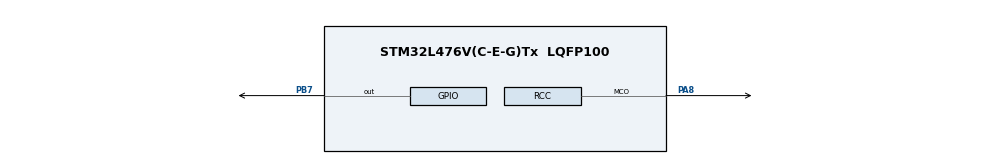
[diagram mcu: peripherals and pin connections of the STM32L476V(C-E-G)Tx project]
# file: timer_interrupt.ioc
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Mcu.Family=STM32L4
RCC.MSI_VALUE=4000000
PH0-OSC_IN\ (PH0).Signal=RCC_OSC_IN
PH1-OSC_OUT\ (PH1).Signal=RCC_OSC_OUT
ProjectManager.StackSize=0x400
ProjectManager.TargetToolchain=STM32CubeIDE
RCC.LSE_VALUE=32768
PH1-OSC_OUT\ (PH1).Mode=HSE-External-Oscillator
RCC.HSE_VALUE=8000000
board=custom
RCC.VCOOutputFreq_Value=32000000
VP_TIM2_VS_ClockSourceINT.Mode=Internal
NVIC.TIM2_IRQn=true\:0\:0\:false\:false\:true\:true\:true
PB7.Signal=GPIO_Output
PA8.Signal=RCC_MCO
TIM2.Period=7200
Mcu.Name=STM32L476V(C-E-G)Tx
Mcu.Package=LQFP100
TIM2.Prescaler=1000
ProjectManager.HeapSize=0x200
RCC.HSI_VALUE=16000000
NVIC.PriorityGroup=NVIC_PRIORITYGROUP_4
TIM2.AutoReloadPreload=TIM_AUTORELOAD_PRELOAD_ENABLE
PA8.Mode=Clock-out
PH0-OSC_IN\ (PH0).Mode=HSE-External-Oscillator

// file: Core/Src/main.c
/* USER CODE BEGIN Header */
/**
  ******************************************************************************
  * @file           : main.c
  * @brief          : Main program body
  ******************************************************************************
  * @attention
  *
  * <h2><center>&copy; Copyright (c) 2020 STMicroelectronics.
  * All rights reserved.</center></h2>
  *
  * This software component is licensed by ST under BSD 3-Clause license,
  * the "License"; You may not use this file except in compliance with the
  * License. You may obtain a copy of the License at:
  *                        opensource.org/licenses/BSD-3-Clause
  *
  ******************************************************************************
  */
/* USER CODE END Header */
#include "main.h"

TIM_HandleTypeDef htim2;

void SystemClock_Config(void);
static void MX_GPIO_Init(void);
static void MX_TIM2_Init(void);

int main(void)
{

  /* MCU Configuration--------------------------------------------------------*/

  /* Reset of all peripherals, Initializes the Flash interface and the Systick. */
  HAL_Init();

  /* Configure the system clock */
  SystemClock_Config();

  /* Initialize all configured peripherals */
  MX_GPIO_Init();
  MX_TIM2_Init();
  /* USER CODE BEGIN 2 */
  HAL_TIM_Base_Start_IT(&htim2);
  /* USER CODE END 2 */

  /* Infinite loop */
  while (1)
  {

  }
}

void SystemClock_Config(void)
{
	  RCC_OscInitTypeDef RCC_OscInitStruct = {0};
	  RCC_ClkInitTypeDef RCC_ClkInitStruct = {0};
	  RCC_PeriphCLKInitTypeDef PeriphClkInit = {0};

	  RCC_OscInitStruct.OscillatorType = RCC_OSCILLATORTYPE_MSI;
	  RCC_OscInitStruct.MSIState = RCC_MSI_ON;
	  RCC_OscInitStruct.MSICalibrationValue = 0;
	  RCC_OscInitStruct.MSIClockRange = RCC_MSIRANGE_6;
	  RCC_OscInitStruct.PLL.PLLState = RCC_PLL_ON;
	  RCC_OscInitStruct.PLL.PLLSource = RCC_PLLSOURCE_MSI;
	  RCC_OscInitStruct.PLL.PLLM = 1;
	  RCC_OscInitStruct.PLL.PLLN = 40;
	  RCC_OscInitStruct.PLL.PLLP = RCC_PLLP_DIV7;
	  RCC_OscInitStruct.PLL.PLLQ = RCC_PLLQ_DIV2;
	  RCC_OscInitStruct.PLL.PLLR = RCC_PLLR_DIV2;
	  if (HAL_RCC_OscConfig(&RCC_OscInitStruct) != HAL_OK) {
	    Error_Handler();
	  }
	  RCC_ClkInitStruct.ClockType = RCC_CLOCKTYPE_HCLK|RCC_CLOCKTYPE_SYSCLK
	                              |RCC_CLOCKTYPE_PCLK1|RCC_CLOCKTYPE_PCLK2;
	  RCC_ClkInitStruct.SYSCLKSource = RCC_SYSCLKSOURCE_PLLCLK;
	  RCC_ClkInitStruct.AHBCLKDivider = RCC_SYSCLK_DIV1;
	  RCC_ClkInitStruct.APB1CLKDivider = RCC_HCLK_DIV1;
	  RCC_ClkInitStruct.APB2CLKDivider = RCC_HCLK_DIV1;

	  if (HAL_RCC_ClockConfig(&RCC_ClkInitStruct, FLASH_LATENCY_4) != HAL_OK) {
	    Error_Handler();
	  }
	  PeriphClkInit.PeriphClockSelection = RCC_PERIPHCLK_USART1|RCC_PERIPHCLK_I2C1
	                              |RCC_PERIPHCLK_I2C2|RCC_PERIPHCLK_I2C3|RCC_PERIPHCLK_USART2;
	  PeriphClkInit.Usart1ClockSelection = RCC_USART1CLKSOURCE_PCLK2;
	  PeriphClkInit.Usart2ClockSelection = RCC_USART2CLKSOURCE_PCLK1;
	  PeriphClkInit.I2c1ClockSelection = RCC_I2C1CLKSOURCE_PCLK1;
	  PeriphClkInit.I2c2ClockSelection = RCC_I2C2CLKSOURCE_PCLK1;
	  PeriphClkInit.I2c3ClockSelection = RCC_I2C3CLKSOURCE_PCLK1;
	  if (HAL_RCCEx_PeriphCLKConfig(&PeriphClkInit) != HAL_OK) {
	    Error_Handler();
	  }
	  /** Configure the main internal regulator output voltage
	  */
	  if (HAL_PWREx_ControlVoltageScaling(PWR_REGULATOR_VOLTAGE_SCALE1) != HAL_OK) {
	    Error_Handler();
	  }
}

static void MX_TIM2_Init(void)
{

  TIM_ClockConfigTypeDef sClockSourceConfig = {0};
  TIM_MasterConfigTypeDef sMasterConfig = {0};

  htim2.Instance = TIM2;
  htim2.Init.Prescaler = 1100;
  htim2.Init.CounterMode = TIM_COUNTERMODE_UP;
  htim2.Init.Period = 7200;
  htim2.Init.ClockDivision = TIM_CLOCKDIVISION_DIV1;
  htim2.Init.AutoReloadPreload = TIM_AUTORELOAD_PRELOAD_ENABLE;
  if (HAL_TIM_Base_Init(&htim2) != HAL_OK)
  {
    Error_Handler();
  }
  sClockSourceConfig.ClockSource = TIM_CLOCKSOURCE_INTERNAL;
  if (HAL_TIM_ConfigClockSource(&htim2, &sClockSourceConfig) != HAL_OK)
  {
    Error_Handler();
  }
  sMasterConfig.MasterOutputTrigger = TIM_TRGO_RESET;
  sMasterConfig.MasterSlaveMode = TIM_MASTERSLAVEMODE_DISABLE;
  if (HAL_TIMEx_MasterConfigSynchronization(&htim2, &sMasterConfig) != HAL_OK)
  {
    Error_Handler();
  }
  /* USER CODE BEGIN TIM2_Init 2 */
  HAL_NVIC_SetPriority(TIM2_IRQn, 1, 0);
  HAL_NVIC_EnableIRQ(TIM2_IRQn);
  /* USER CODE END TIM2_Init 2 */

}

static void MX_GPIO_Init(void)
{
  GPIO_InitTypeDef GPIO_InitStruct = {0};

  /* GPIO Ports Clock Enable */
  __HAL_RCC_GPIOH_CLK_ENABLE();
  __HAL_RCC_GPIOA_CLK_ENABLE();
  __HAL_RCC_GPIOB_CLK_ENABLE();

  /*Configure GPIO pin Output Level */
  HAL_GPIO_WritePin(GPIOB, GPIO_PIN_7, GPIO_PIN_RESET);

  /*Configure GPIO pin : PA8 */
  GPIO_InitStruct.Pin = GPIO_PIN_8;
  GPIO_InitStruct.Mode = GPIO_MODE_AF_PP;
  GPIO_InitStruct.Pull = GPIO_NOPULL;
  GPIO_InitStruct.Speed = GPIO_SPEED_FREQ_LOW;
  GPIO_InitStruct.Alternate = GPIO_AF0_MCO;
  HAL_GPIO_Init(GPIOA, &GPIO_InitStruct);

  /*Configure GPIO pin : PB7 */
  GPIO_InitStruct.Pin = GPIO_PIN_7;
  GPIO_InitStruct.Mode = GPIO_MODE_OUTPUT_PP;
  GPIO_InitStruct.Pull = GPIO_NOPULL;
  GPIO_InitStruct.Speed = GPIO_SPEED_FREQ_LOW;
  HAL_GPIO_Init(GPIOB, &GPIO_InitStruct);

}

/* USER CODE BEGIN 4 */

void TIM2_IRQHandler(void) {
    if(TIM2->SR & TIM_SR_UIF) {    // check status
        HAL_GPIO_WritePin(GPIOB, GPIO_PIN_7, GPIO_PIN_SET);
        HAL_Delay(1);
        HAL_GPIO_WritePin(GPIOB, GPIO_PIN_7, GPIO_PIN_RESET);

        //HAL_TIM_IRQHandler(&htim2);

        TIM2->SR &= ~TIM_SR_UIF;   // clear status
    }
}

/* USER CODE END 4 */

void Error_Handler(void)
{
}

/************************ (C) COPYRIGHT STMicroelectronics *****END OF FILE****/
